VERSION 5.7 ;
  NOWIREEXTENSIONATPIN ON ;
  DIVIDERCHAR "/" ;
  BUSBITCHARS "[]" ;
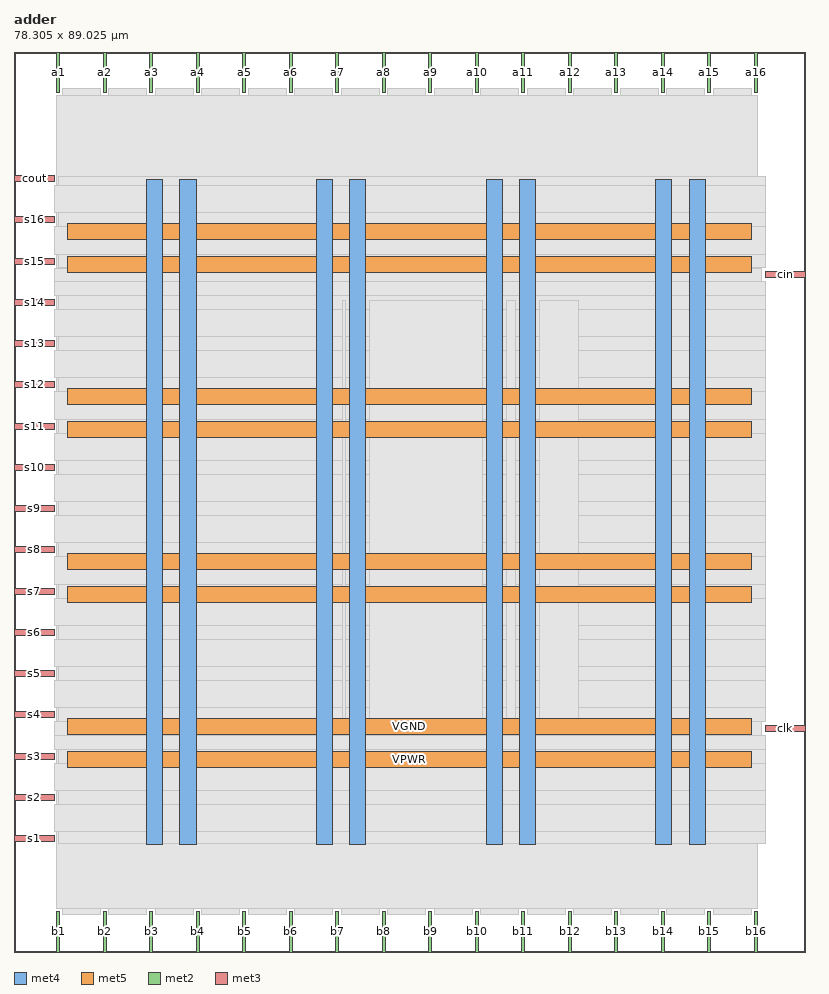
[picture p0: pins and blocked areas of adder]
MACRO adder
  CLASS BLOCK ;
  FOREIGN adder ;
  ORIGIN 0.000 0.000 ;
  SIZE 78.305 BY 89.025 ;
  PIN VGND
    DIRECTION INOUT ;
    USE GROUND ;
    PORT
      LAYER met4 ;
        RECT 16.415 10.640 18.015 76.400 ;
    END
    PORT
      LAYER met4 ;
        RECT 33.205 10.640 34.805 76.400 ;
    END
    PORT
      LAYER met4 ;
        RECT 49.995 10.640 51.595 76.400 ;
    END
    PORT
      LAYER met4 ;
        RECT 66.785 10.640 68.385 76.400 ;
    END
    PORT
      LAYER met5 ;
        RECT 5.280 21.540 72.920 23.140 ;
    END
    PORT
      LAYER met5 ;
        RECT 5.280 37.860 72.920 39.460 ;
    END
    PORT
      LAYER met5 ;
        RECT 5.280 54.180 72.920 55.780 ;
    END
    PORT
      LAYER met5 ;
        RECT 5.280 70.500 72.920 72.100 ;
    END
  END VGND
  PIN VPWR
    DIRECTION INOUT ;
    USE POWER ;
    PORT
      LAYER met4 ;
        RECT 13.115 10.640 14.715 76.400 ;
    END
    PORT
      LAYER met4 ;
        RECT 29.905 10.640 31.505 76.400 ;
    END
    PORT
      LAYER met4 ;
        RECT 46.695 10.640 48.295 76.400 ;
    END
    PORT
      LAYER met4 ;
        RECT 63.485 10.640 65.085 76.400 ;
    END
    PORT
      LAYER met5 ;
        RECT 5.280 18.240 72.920 19.840 ;
    END
    PORT
      LAYER met5 ;
        RECT 5.280 34.560 72.920 36.160 ;
    END
    PORT
      LAYER met5 ;
        RECT 5.280 50.880 72.920 52.480 ;
    END
    PORT
      LAYER met5 ;
        RECT 5.280 67.200 72.920 68.800 ;
    END
  END VPWR
  PIN a1
    DIRECTION INPUT ;
    USE SIGNAL ;
    ANTENNAGATEAREA 0.196500 ;
    PORT
      LAYER met2 ;
        RECT 4.230 85.025 4.510 89.025 ;
    END
  END a1
  PIN a10
    DIRECTION INPUT ;
    USE SIGNAL ;
    ANTENNAGATEAREA 0.196500 ;
    PORT
      LAYER met2 ;
        RECT 45.630 85.025 45.910 89.025 ;
    END
  END a10
  PIN a11
    DIRECTION INPUT ;
    USE SIGNAL ;
    ANTENNAGATEAREA 0.196500 ;
    PORT
      LAYER met2 ;
        RECT 50.230 85.025 50.510 89.025 ;
    END
  END a11
  PIN a12
    DIRECTION INPUT ;
    USE SIGNAL ;
    ANTENNAGATEAREA 0.196500 ;
    PORT
      LAYER met2 ;
        RECT 54.830 85.025 55.110 89.025 ;
    END
  END a12
  PIN a13
    DIRECTION INPUT ;
    USE SIGNAL ;
    ANTENNAGATEAREA 0.196500 ;
    PORT
      LAYER met2 ;
        RECT 59.430 85.025 59.710 89.025 ;
    END
  END a13
  PIN a14
    DIRECTION INPUT ;
    USE SIGNAL ;
    ANTENNAGATEAREA 0.196500 ;
    PORT
      LAYER met2 ;
        RECT 64.030 85.025 64.310 89.025 ;
    END
  END a14
  PIN a15
    DIRECTION INPUT ;
    USE SIGNAL ;
    ANTENNAGATEAREA 0.196500 ;
    PORT
      LAYER met2 ;
        RECT 68.630 85.025 68.910 89.025 ;
    END
  END a15
  PIN a16
    DIRECTION INPUT ;
    USE SIGNAL ;
    ANTENNAGATEAREA 0.196500 ;
    PORT
      LAYER met2 ;
        RECT 73.230 85.025 73.510 89.025 ;
    END
  END a16
  PIN a2
    DIRECTION INPUT ;
    USE SIGNAL ;
    ANTENNAGATEAREA 0.196500 ;
    PORT
      LAYER met2 ;
        RECT 8.830 85.025 9.110 89.025 ;
    END
  END a2
  PIN a3
    DIRECTION INPUT ;
    USE SIGNAL ;
    ANTENNAGATEAREA 0.196500 ;
    PORT
      LAYER met2 ;
        RECT 13.430 85.025 13.710 89.025 ;
    END
  END a3
  PIN a4
    DIRECTION INPUT ;
    USE SIGNAL ;
    ANTENNAGATEAREA 0.196500 ;
    PORT
      LAYER met2 ;
        RECT 18.030 85.025 18.310 89.025 ;
    END
  END a4
  PIN a5
    DIRECTION INPUT ;
    USE SIGNAL ;
    ANTENNAGATEAREA 0.196500 ;
    PORT
      LAYER met2 ;
        RECT 22.630 85.025 22.910 89.025 ;
    END
  END a5
  PIN a6
    DIRECTION INPUT ;
    USE SIGNAL ;
    ANTENNAGATEAREA 0.196500 ;
    PORT
      LAYER met2 ;
        RECT 27.230 85.025 27.510 89.025 ;
    END
  END a6
  PIN a7
    DIRECTION INPUT ;
    USE SIGNAL ;
    ANTENNAGATEAREA 0.196500 ;
    PORT
      LAYER met2 ;
        RECT 31.830 85.025 32.110 89.025 ;
    END
  END a7
  PIN a8
    DIRECTION INPUT ;
    USE SIGNAL ;
    ANTENNAGATEAREA 0.196500 ;
    PORT
      LAYER met2 ;
        RECT 36.430 85.025 36.710 89.025 ;
    END
  END a8
  PIN a9
    DIRECTION INPUT ;
    USE SIGNAL ;
    ANTENNAGATEAREA 0.196500 ;
    PORT
      LAYER met2 ;
        RECT 41.030 85.025 41.310 89.025 ;
    END
  END a9
  PIN b1
    DIRECTION INPUT ;
    USE SIGNAL ;
    ANTENNAGATEAREA 0.196500 ;
    PORT
      LAYER met2 ;
        RECT 4.230 0.000 4.510 4.000 ;
    END
  END b1
  PIN b10
    DIRECTION INPUT ;
    USE SIGNAL ;
    ANTENNAGATEAREA 0.196500 ;
    PORT
      LAYER met2 ;
        RECT 45.630 0.000 45.910 4.000 ;
    END
  END b10
  PIN b11
    DIRECTION INPUT ;
    USE SIGNAL ;
    ANTENNAGATEAREA 0.196500 ;
    PORT
      LAYER met2 ;
        RECT 50.230 0.000 50.510 4.000 ;
    END
  END b11
  PIN b12
    DIRECTION INPUT ;
    USE SIGNAL ;
    ANTENNAGATEAREA 0.196500 ;
    PORT
      LAYER met2 ;
        RECT 54.830 0.000 55.110 4.000 ;
    END
  END b12
  PIN b13
    DIRECTION INPUT ;
    USE SIGNAL ;
    ANTENNAGATEAREA 0.196500 ;
    PORT
      LAYER met2 ;
        RECT 59.430 0.000 59.710 4.000 ;
    END
  END b13
  PIN b14
    DIRECTION INPUT ;
    USE SIGNAL ;
    ANTENNAGATEAREA 0.196500 ;
    PORT
      LAYER met2 ;
        RECT 64.030 0.000 64.310 4.000 ;
    END
  END b14
  PIN b15
    DIRECTION INPUT ;
    USE SIGNAL ;
    ANTENNAGATEAREA 0.196500 ;
    PORT
      LAYER met2 ;
        RECT 68.630 0.000 68.910 4.000 ;
    END
  END b15
  PIN b16
    DIRECTION INPUT ;
    USE SIGNAL ;
    ANTENNAGATEAREA 0.196500 ;
    PORT
      LAYER met2 ;
        RECT 73.230 0.000 73.510 4.000 ;
    END
  END b16
  PIN b2
    DIRECTION INPUT ;
    USE SIGNAL ;
    ANTENNAGATEAREA 0.196500 ;
    PORT
      LAYER met2 ;
        RECT 8.830 0.000 9.110 4.000 ;
    END
  END b2
  PIN b3
    DIRECTION INPUT ;
    USE SIGNAL ;
    ANTENNAGATEAREA 0.196500 ;
    PORT
      LAYER met2 ;
        RECT 13.430 0.000 13.710 4.000 ;
    END
  END b3
  PIN b4
    DIRECTION INPUT ;
    USE SIGNAL ;
    ANTENNAGATEAREA 0.196500 ;
    PORT
      LAYER met2 ;
        RECT 18.030 0.000 18.310 4.000 ;
    END
  END b4
  PIN b5
    DIRECTION INPUT ;
    USE SIGNAL ;
    ANTENNAGATEAREA 0.196500 ;
    PORT
      LAYER met2 ;
        RECT 22.630 0.000 22.910 4.000 ;
    END
  END b5
  PIN b6
    DIRECTION INPUT ;
    USE SIGNAL ;
    ANTENNAGATEAREA 0.196500 ;
    PORT
      LAYER met2 ;
        RECT 27.230 0.000 27.510 4.000 ;
    END
  END b6
  PIN b7
    DIRECTION INPUT ;
    USE SIGNAL ;
    ANTENNAGATEAREA 0.196500 ;
    PORT
      LAYER met2 ;
        RECT 31.830 0.000 32.110 4.000 ;
    END
  END b7
  PIN b8
    DIRECTION INPUT ;
    USE SIGNAL ;
    ANTENNAGATEAREA 0.196500 ;
    PORT
      LAYER met2 ;
        RECT 36.430 0.000 36.710 4.000 ;
    END
  END b8
  PIN b9
    DIRECTION INPUT ;
    USE SIGNAL ;
    ANTENNAGATEAREA 0.196500 ;
    PORT
      LAYER met2 ;
        RECT 41.030 0.000 41.310 4.000 ;
    END
  END b9
  PIN cin
    DIRECTION INPUT ;
    USE SIGNAL ;
    ANTENNAGATEAREA 0.196500 ;
    PORT
      LAYER met3 ;
        RECT 74.305 66.680 78.305 67.280 ;
    END
  END cin
  PIN clk
    DIRECTION INPUT ;
    USE SIGNAL ;
    ANTENNAGATEAREA 0.852000 ;
    PORT
      LAYER met3 ;
        RECT 74.305 21.800 78.305 22.400 ;
    END
  END clk
  PIN cout
    DIRECTION OUTPUT ;
    USE SIGNAL ;
    ANTENNADIFFAREA 0.340600 ;
    PORT
      LAYER met3 ;
        RECT 0.000 76.200 4.000 76.800 ;
    END
  END cout
  PIN s1
    DIRECTION OUTPUT ;
    USE SIGNAL ;
    ANTENNADIFFAREA 0.340600 ;
    PORT
      LAYER met3 ;
        RECT 0.000 10.920 4.000 11.520 ;
    END
  END s1
  PIN s10
    DIRECTION OUTPUT ;
    USE SIGNAL ;
    ANTENNADIFFAREA 0.340600 ;
    PORT
      LAYER met3 ;
        RECT 0.000 47.640 4.000 48.240 ;
    END
  END s10
  PIN s11
    DIRECTION OUTPUT ;
    USE SIGNAL ;
    ANTENNADIFFAREA 0.340600 ;
    PORT
      LAYER met3 ;
        RECT 0.000 51.720 4.000 52.320 ;
    END
  END s11
  PIN s12
    DIRECTION OUTPUT ;
    USE SIGNAL ;
    ANTENNADIFFAREA 0.340600 ;
    PORT
      LAYER met3 ;
        RECT 0.000 55.800 4.000 56.400 ;
    END
  END s12
  PIN s13
    DIRECTION OUTPUT ;
    USE SIGNAL ;
    ANTENNADIFFAREA 0.340600 ;
    PORT
      LAYER met3 ;
        RECT 0.000 59.880 4.000 60.480 ;
    END
  END s13
  PIN s14
    DIRECTION OUTPUT ;
    USE SIGNAL ;
    ANTENNADIFFAREA 0.340600 ;
    PORT
      LAYER met3 ;
        RECT 0.000 63.960 4.000 64.560 ;
    END
  END s14
  PIN s15
    DIRECTION OUTPUT ;
    USE SIGNAL ;
    ANTENNADIFFAREA 0.340600 ;
    PORT
      LAYER met3 ;
        RECT 0.000 68.040 4.000 68.640 ;
    END
  END s15
  PIN s16
    DIRECTION OUTPUT ;
    USE SIGNAL ;
    ANTENNADIFFAREA 0.340600 ;
    PORT
      LAYER met3 ;
        RECT 0.000 72.120 4.000 72.720 ;
    END
  END s16
  PIN s2
    DIRECTION OUTPUT ;
    USE SIGNAL ;
    ANTENNADIFFAREA 0.340600 ;
    PORT
      LAYER met3 ;
        RECT 0.000 15.000 4.000 15.600 ;
    END
  END s2
  PIN s3
    DIRECTION OUTPUT ;
    USE SIGNAL ;
    ANTENNADIFFAREA 0.340600 ;
    PORT
      LAYER met3 ;
        RECT 0.000 19.080 4.000 19.680 ;
    END
  END s3
  PIN s4
    DIRECTION OUTPUT ;
    USE SIGNAL ;
    ANTENNADIFFAREA 0.340600 ;
    PORT
      LAYER met3 ;
        RECT 0.000 23.160 4.000 23.760 ;
    END
  END s4
  PIN s5
    DIRECTION OUTPUT ;
    USE SIGNAL ;
    ANTENNADIFFAREA 0.340600 ;
    PORT
      LAYER met3 ;
        RECT 0.000 27.240 4.000 27.840 ;
    END
  END s5
  PIN s6
    DIRECTION OUTPUT ;
    USE SIGNAL ;
    ANTENNADIFFAREA 0.340600 ;
    PORT
      LAYER met3 ;
        RECT 0.000 31.320 4.000 31.920 ;
    END
  END s6
  PIN s7
    DIRECTION OUTPUT ;
    USE SIGNAL ;
    ANTENNADIFFAREA 0.340600 ;
    PORT
      LAYER met3 ;
        RECT 0.000 35.400 4.000 36.000 ;
    END
  END s7
  PIN s8
    DIRECTION OUTPUT ;
    USE SIGNAL ;
    ANTENNADIFFAREA 0.340600 ;
    PORT
      LAYER met3 ;
        RECT 0.000 39.480 4.000 40.080 ;
    END
  END s8
  PIN s9
    DIRECTION OUTPUT ;
    USE SIGNAL ;
    ANTENNADIFFAREA 0.340600 ;
    PORT
      LAYER met3 ;
        RECT 0.000 43.560 4.000 44.160 ;
    END
  END s9
  OBS
      LAYER nwell ;
        RECT 5.330 10.795 72.870 76.245 ;
      LAYER li1 ;
        RECT 5.520 10.795 72.680 76.245 ;
      LAYER met1 ;
        RECT 4.210 10.640 73.530 76.400 ;
      LAYER met2 ;
        RECT 4.790 84.745 8.550 85.410 ;
        RECT 9.390 84.745 13.150 85.410 ;
        RECT 13.990 84.745 17.750 85.410 ;
        RECT 18.590 84.745 22.350 85.410 ;
        RECT 23.190 84.745 26.950 85.410 ;
        RECT 27.790 84.745 31.550 85.410 ;
        RECT 32.390 84.745 36.150 85.410 ;
        RECT 36.990 84.745 40.750 85.410 ;
        RECT 41.590 84.745 45.350 85.410 ;
        RECT 46.190 84.745 49.950 85.410 ;
        RECT 50.790 84.745 54.550 85.410 ;
        RECT 55.390 84.745 59.150 85.410 ;
        RECT 59.990 84.745 63.750 85.410 ;
        RECT 64.590 84.745 68.350 85.410 ;
        RECT 69.190 84.745 72.950 85.410 ;
        RECT 4.230 4.280 73.500 84.745 ;
        RECT 4.790 3.670 8.550 4.280 ;
        RECT 9.390 3.670 13.150 4.280 ;
        RECT 13.990 3.670 17.750 4.280 ;
        RECT 18.590 3.670 22.350 4.280 ;
        RECT 23.190 3.670 26.950 4.280 ;
        RECT 27.790 3.670 31.550 4.280 ;
        RECT 32.390 3.670 36.150 4.280 ;
        RECT 36.990 3.670 40.750 4.280 ;
        RECT 41.590 3.670 45.350 4.280 ;
        RECT 46.190 3.670 49.950 4.280 ;
        RECT 50.790 3.670 54.550 4.280 ;
        RECT 55.390 3.670 59.150 4.280 ;
        RECT 59.990 3.670 63.750 4.280 ;
        RECT 64.590 3.670 68.350 4.280 ;
        RECT 69.190 3.670 72.950 4.280 ;
      LAYER met3 ;
        RECT 4.400 75.800 74.305 76.665 ;
        RECT 3.990 73.120 74.305 75.800 ;
        RECT 4.400 71.720 74.305 73.120 ;
        RECT 3.990 69.040 74.305 71.720 ;
        RECT 4.400 67.680 74.305 69.040 ;
        RECT 4.400 67.640 73.905 67.680 ;
        RECT 3.990 66.280 73.905 67.640 ;
        RECT 3.990 64.960 74.305 66.280 ;
        RECT 4.400 63.560 74.305 64.960 ;
        RECT 3.990 60.880 74.305 63.560 ;
        RECT 4.400 59.480 74.305 60.880 ;
        RECT 3.990 56.800 74.305 59.480 ;
        RECT 4.400 55.400 74.305 56.800 ;
        RECT 3.990 52.720 74.305 55.400 ;
        RECT 4.400 51.320 74.305 52.720 ;
        RECT 3.990 48.640 74.305 51.320 ;
        RECT 4.400 47.240 74.305 48.640 ;
        RECT 3.990 44.560 74.305 47.240 ;
        RECT 4.400 43.160 74.305 44.560 ;
        RECT 3.990 40.480 74.305 43.160 ;
        RECT 4.400 39.080 74.305 40.480 ;
        RECT 3.990 36.400 74.305 39.080 ;
        RECT 4.400 35.000 74.305 36.400 ;
        RECT 3.990 32.320 74.305 35.000 ;
        RECT 4.400 30.920 74.305 32.320 ;
        RECT 3.990 28.240 74.305 30.920 ;
        RECT 4.400 26.840 74.305 28.240 ;
        RECT 3.990 24.160 74.305 26.840 ;
        RECT 4.400 22.800 74.305 24.160 ;
        RECT 4.400 22.760 73.905 22.800 ;
        RECT 3.990 21.400 73.905 22.760 ;
        RECT 3.990 20.080 74.305 21.400 ;
        RECT 4.400 18.680 74.305 20.080 ;
        RECT 3.990 16.000 74.305 18.680 ;
        RECT 4.400 14.600 74.305 16.000 ;
        RECT 3.990 11.920 74.305 14.600 ;
        RECT 4.400 10.715 74.305 11.920 ;
      LAYER met4 ;
        RECT 32.495 22.615 32.805 64.425 ;
        RECT 35.205 22.615 46.295 64.425 ;
        RECT 48.695 22.615 49.595 64.425 ;
        RECT 51.995 22.615 55.825 64.425 ;
  END
END adder
END LIBRARY

